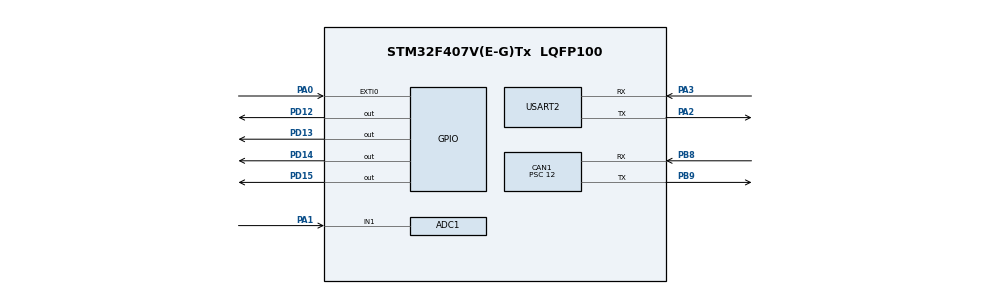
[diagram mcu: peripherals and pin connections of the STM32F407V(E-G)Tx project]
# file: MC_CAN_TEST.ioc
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ADC1.Channel-0\#ChannelRegularConversion=ADC_CHANNEL_1
ADC1.ContinuousConvMode=ENABLE
ADC1.NbrOfConversionFlag=1
ADC1.Rank-0\#ChannelRegularConversion=1
ADC1.SamplingTime-0\#ChannelRegularConversion=ADC_SAMPLETIME_3CYCLES
ADC1.ScanConvMode=ENABLE
ADC1.master=1
CAN1.BS1=CAN_BS1_11TQ
CAN1.BS2=CAN_BS2_2TQ
CAN1.CalculateBaudRate=250000
CAN1.CalculateTimeBit=4000
CAN1.CalculateTimeQuantum=285.7142857142857
CAN1.Prescaler=12
Mcu.Family=STM32F4
Mcu.Name=STM32F407V(E-G)Tx
Mcu.Package=LQFP100
NVIC.CAN1_RX0_IRQn=true\:0\:2\:false\:false\:true\:true\:true
NVIC.EXTI0_IRQn=true\:0\:1\:false\:false\:true\:true\:true
NVIC.PriorityGroup=NVIC_PRIORITYGROUP_0
PA0-WKUP.Signal=GPXTI0
PA1.Signal=ADCx_IN1
PA2.Mode=Asynchronous
PA2.Signal=USART2_TX
PA3.Mode=Asynchronous
PA3.Signal=USART2_RX
PB8.Mode=CAN_Activate
PB8.Signal=CAN1_RX
PB9.Mode=CAN_Activate
PB9.Signal=CAN1_TX
PD12.Signal=GPIO_Output
PD13.Signal=GPIO_Output
PD14.Signal=GPIO_Output
PD15.Signal=GPIO_Output
PH0-OSC_IN.Mode=HSE-External-Oscillator
PH0-OSC_IN.Signal=RCC_OSC_IN
PH1-OSC_OUT.Mode=HSE-External-Oscillator
PH1-OSC_OUT.Signal=RCC_OSC_OUT
ProjectManager.HeapSize=0x200
ProjectManager.StackSize=0x400
ProjectManager.TargetToolchain=STM32CubeIDE
RCC.48MHZClocksFreq_Value=48000000
RCC.AHBFreq_Value=168000000
RCC.APB1CLKDivider=RCC_HCLK_DIV4
RCC.APB1Freq_Value=42000000
RCC.APB1TimFreq_Value=84000000
RCC.APB2CLKDivider=RCC_HCLK_DIV2
RCC.APB2Freq_Value=84000000
RCC.APB2TimFreq_Value=168000000
RCC.CortexFreq_Value=168000000
RCC.HCLKFreq_Value=168000000
RCC.HSE_VALUE=8000000
RCC.HSI_VALUE=16000000
RCC.LSE_VALUE=32768
RCC.PLLM=4
RCC.PLLN=168
RCC.PLLQ=7
RCC.PLLSourceVirtual=RCC_PLLSOURCE_HSE
RCC.SYSCLKFreq_VALUE=168000000
RCC.SYSCLKSource=RCC_SYSCLKSOURCE_PLLCLK
RCC.VCOOutputFreq_Value=336000000
SH.ADCx_IN1.0=ADC1_IN1,IN1
USART2.VirtualMode=VM_ASYNC
board=STM32F407G-DISC1

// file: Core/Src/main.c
/* USER CODE BEGIN Header */
/**
 ******************************************************************************
 * @file           : main.c
 * @brief          : Main program body
 ******************************************************************************
 * @attention
 *
 * <h2><center>&copy; Copyright (c) 2021 STMicroelectronics.
 * All rights reserved.</center></h2>
 *
 * This software component is licensed by ST under Ultimate Liberty license
 * SLA0044, the "License"; You may not use this file except in compliance with
 * the License. You may obtain a copy of the License at:
 *                             www.st.com/SLA0044
 *
 ******************************************************************************
 */
/* USER CODE END Header */
#include "main.h"
#include "usb_device.h"

ADC_HandleTypeDef hadc1;

CAN_HandleTypeDef hcan1;

UART_HandleTypeDef huart2;

/* USER CODE BEGIN PV */
CAN_TxHeaderTypeDef pTxHeader; //CAN Tx Header
CAN_RxHeaderTypeDef pRxHeader; //CAN Rx Header
uint32_t pTxMailbox;
CAN_FilterTypeDef sFilterConfig; //CAN filter configuration

uint32_t MC_RX = 0x181;
uint32_t MC_TX = 0x201;

uint8_t sensor_raw;
// Byte 0: REG ID, Byte 1,2: Data
uint8_t rcvData[8];
uint8_t tData[8];
uint32_t rcvDataVal;
/* USER CODE END PV */

void SystemClock_Config(void);
static void MX_GPIO_Init(void);
static void MX_CAN1_Init(void);
static void MX_ADC1_Init(void);
static void MX_USART2_UART_Init(void);
/* USER CODE BEGIN PFP */
static void CAN_TxHeader_Init(CAN_TxHeaderTypeDef *pTxHeader, uint32_t dlc, uint32_t ide, uint32_t rtr, uint32_t stdId);
static void CAN_Filter_Init(CAN_HandleTypeDef *hcan, CAN_FilterTypeDef *sFilterConfig, uint32_t fifo, uint32_t highId, uint32_t lowId, uint32_t highMask, uint32_t lowMask, uint32_t scale);
HAL_StatusTypeDef CANsend(CAN_HandleTypeDef *hcan, CAN_TxHeaderTypeDef *pTxHeader, uint8_t data[], uint32_t *pTxMailbox);
/* USER CODE END PFP */

int main(void)
{

  /* MCU Configuration--------------------------------------------------------*/

  /* Reset of all peripherals, Initializes the Flash interface and the Systick. */
  HAL_Init();

  /* Configure the system clock */
  SystemClock_Config();

  /* Initialize all configured peripherals */
  MX_GPIO_Init();
  MX_CAN1_Init();
  MX_ADC1_Init();
  MX_USART2_UART_Init();
  MX_USB_DEVICE_Init();
  /* USER CODE BEGIN 2 */

	//Initialize CAN header - standard id type, set standard Id = filter ID of other device
	CAN_TxHeader_Init(&pTxHeader, 3, CAN_ID_STD, CAN_RTR_DATA, MC_TX);

	//Initialize CAN filter - filter ID = TxHeader Id of other device, 32 bit scale. Enables and configs filter.
	CAN_Filter_Init(&hcan1, &sFilterConfig, CAN_FILTER_FIFO0, MC_RX, 0, 0, 0, CAN_FILTERSCALE_32BIT);

	//start CAN
	HAL_CAN_Start(&hcan1);

	//interrupt on message pending
	HAL_CAN_ActivateNotification(&hcan1, CAN_IT_RX_FIFO0_MSG_PENDING);

  /* USER CODE END 2 */

  /* Infinite loop */
  /* USER CODE BEGIN WHILE */
	while (1)
	{
		HAL_ADC_Start(&hadc1);
		HAL_ADC_PollForConversion(&hadc1, 1000);
		sensor_raw = HAL_ADC_GetValue(&hadc1);
    /* USER CODE END WHILE */

	}
}

void SystemClock_Config(void)
{
  RCC_OscInitTypeDef RCC_OscInitStruct = {0};
  RCC_ClkInitTypeDef RCC_ClkInitStruct = {0};

  /** Configure the main internal regulator output voltage
  */
  __HAL_RCC_PWR_CLK_ENABLE();
  __HAL_PWR_VOLTAGESCALING_CONFIG(PWR_REGULATOR_VOLTAGE_SCALE1);
  /** Initializes the RCC Oscillators according to the specified parameters
  * in the RCC_OscInitTypeDef structure.
  */
  RCC_OscInitStruct.OscillatorType = RCC_OSCILLATORTYPE_HSE;
  RCC_OscInitStruct.HSEState = RCC_HSE_ON;
  RCC_OscInitStruct.PLL.PLLState = RCC_PLL_ON;
  RCC_OscInitStruct.PLL.PLLSource = RCC_PLLSOURCE_HSE;
  RCC_OscInitStruct.PLL.PLLM = 13;
  RCC_OscInitStruct.PLL.PLLN = 168;
  RCC_OscInitStruct.PLL.PLLP = RCC_PLLP_DIV2;
  RCC_OscInitStruct.PLL.PLLQ = 7;
  if (HAL_RCC_OscConfig(&RCC_OscInitStruct) != HAL_OK)
  {
    Error_Handler();
  }
  /** Initializes the CPU, AHB and APB buses clocks
  */
  RCC_ClkInitStruct.ClockType = RCC_CLOCKTYPE_HCLK|RCC_CLOCKTYPE_SYSCLK
                              |RCC_CLOCKTYPE_PCLK1|RCC_CLOCKTYPE_PCLK2;
  RCC_ClkInitStruct.SYSCLKSource = RCC_SYSCLKSOURCE_PLLCLK;
  RCC_ClkInitStruct.AHBCLKDivider = RCC_SYSCLK_DIV1;
  RCC_ClkInitStruct.APB1CLKDivider = RCC_HCLK_DIV4;
  RCC_ClkInitStruct.APB2CLKDivider = RCC_HCLK_DIV2;

  if (HAL_RCC_ClockConfig(&RCC_ClkInitStruct, FLASH_LATENCY_5) != HAL_OK)
  {
    Error_Handler();
  }
}

static void MX_ADC1_Init(void)
{

  ADC_ChannelConfTypeDef sConfig = {0};

  /** Configure the global features of the ADC (Clock, Resolution, Data Alignment and number of conversion)
  */
  hadc1.Instance = ADC1;
  hadc1.Init.ClockPrescaler = ADC_CLOCK_SYNC_PCLK_DIV4;
  hadc1.Init.Resolution = ADC_RESOLUTION_12B;
  hadc1.Init.ScanConvMode = ENABLE;
  hadc1.Init.ContinuousConvMode = ENABLE;
  hadc1.Init.DiscontinuousConvMode = DISABLE;
  hadc1.Init.ExternalTrigConvEdge = ADC_EXTERNALTRIGCONVEDGE_NONE;
  hadc1.Init.ExternalTrigConv = ADC_SOFTWARE_START;
  hadc1.Init.DataAlign = ADC_DATAALIGN_RIGHT;
  hadc1.Init.NbrOfConversion = 1;
  hadc1.Init.DMAContinuousRequests = DISABLE;
  hadc1.Init.EOCSelection = ADC_EOC_SINGLE_CONV;
  if (HAL_ADC_Init(&hadc1) != HAL_OK)
  {
    Error_Handler();
  }
  /** Configure for the selected ADC regular channel its corresponding rank in the sequencer and its sample time.
  */
  sConfig.Channel = ADC_CHANNEL_1;
  sConfig.Rank = 1;
  sConfig.SamplingTime = ADC_SAMPLETIME_3CYCLES;
  if (HAL_ADC_ConfigChannel(&hadc1, &sConfig) != HAL_OK)
  {
    Error_Handler();
  }

}

static void MX_CAN1_Init(void)
{

  hcan1.Instance = CAN1;
  hcan1.Init.Prescaler = 12;
  hcan1.Init.Mode = CAN_MODE_NORMAL;
  hcan1.Init.SyncJumpWidth = CAN_SJW_1TQ;
  hcan1.Init.TimeSeg1 = CAN_BS1_11TQ;
  hcan1.Init.TimeSeg2 = CAN_BS2_2TQ;
  hcan1.Init.TimeTriggeredMode = DISABLE;
  hcan1.Init.AutoBusOff = DISABLE;
  hcan1.Init.AutoWakeUp = DISABLE;
  hcan1.Init.AutoRetransmission = DISABLE;
  hcan1.Init.ReceiveFifoLocked = DISABLE;
  hcan1.Init.TransmitFifoPriority = DISABLE;
  if (HAL_CAN_Init(&hcan1) != HAL_OK)
  {
    Error_Handler();
  }

}

static void MX_USART2_UART_Init(void)
{

  huart2.Instance = USART2;
  huart2.Init.BaudRate = 115200;
  huart2.Init.WordLength = UART_WORDLENGTH_8B;
  huart2.Init.StopBits = UART_STOPBITS_1;
  huart2.Init.Parity = UART_PARITY_NONE;
  huart2.Init.Mode = UART_MODE_TX_RX;
  huart2.Init.HwFlowCtl = UART_HWCONTROL_NONE;
  huart2.Init.OverSampling = UART_OVERSAMPLING_16;
  if (HAL_UART_Init(&huart2) != HAL_OK)
  {
    Error_Handler();
  }

}

static void MX_GPIO_Init(void)
{
  GPIO_InitTypeDef GPIO_InitStruct = {0};

  /* GPIO Ports Clock Enable */
  __HAL_RCC_GPIOH_CLK_ENABLE();
  __HAL_RCC_GPIOA_CLK_ENABLE();
  __HAL_RCC_GPIOD_CLK_ENABLE();
  __HAL_RCC_GPIOB_CLK_ENABLE();

  /*Configure GPIO pin Output Level */
  HAL_GPIO_WritePin(GPIOD, GPIO_PIN_12|GPIO_PIN_13|GPIO_PIN_14|GPIO_PIN_15, GPIO_PIN_RESET);

  /*Configure GPIO pin : PA0 */
  GPIO_InitStruct.Pin = GPIO_PIN_0;
  GPIO_InitStruct.Mode = GPIO_MODE_IT_RISING;
  GPIO_InitStruct.Pull = GPIO_NOPULL;
  HAL_GPIO_Init(GPIOA, &GPIO_InitStruct);

  /*Configure GPIO pins : PD12 PD13 PD14 PD15 */
  GPIO_InitStruct.Pin = GPIO_PIN_12|GPIO_PIN_13|GPIO_PIN_14|GPIO_PIN_15;
  GPIO_InitStruct.Mode = GPIO_MODE_OUTPUT_PP;
  GPIO_InitStruct.Pull = GPIO_NOPULL;
  GPIO_InitStruct.Speed = GPIO_SPEED_FREQ_LOW;
  HAL_GPIO_Init(GPIOD, &GPIO_InitStruct);

  /* EXTI interrupt init*/
  HAL_NVIC_SetPriority(EXTI0_IRQn, 0, 1);
  HAL_NVIC_EnableIRQ(EXTI0_IRQn);

}

/* USER CODE BEGIN 4 */
static void CAN_TxHeader_Init(CAN_TxHeaderTypeDef *pTxHeader, uint32_t dlc,
		uint32_t ide, uint32_t rtr, uint32_t stdId)
{
	pTxHeader->DLC = dlc; // 'dlc' bytes of data
	pTxHeader->IDE = ide;
	pTxHeader->RTR = rtr;
	pTxHeader->StdId = stdId; //set standard identifier.
}

/**
 * @brief CAN Filter Initialization Function
 * @param hcan          : pointer to a CAN_HandleTypeDef structure that contains the configuration information for the specified CAN.
 *        sFilterConfig : pointer to a CAN_FilterTypeDef structure.
 * 	   fifo          : Specifies the FIFO (0 or 1) which will be assigned to the filter. This parameter can be a value of CAN_filter_FIFO
 * 	   highID        : Specifies the filter identification number (MSBs for a 32-bit configuration, first one for a 16-bit configuration). This parameter can be a value between 0x0000 and 0xFFFF
 * 	   lowID         : Specifies the filter identification number (LSBs for a 32-bit configuration, second one for a 16-bit configuration). This parameter can be a value between 0x0000 and 0xFFFF
 * 	   highMask      : Specifies the filter mask number or identification number, according to the mode (MSBs for a 32-bit configuration, first one for a 16-bit configuration). This parameter can be a value between 0x0000 and 0xFFFF
 * 	   lowMask       : Specifies the filter mask number or identification number, according to the mode (LSBs for a 32-bit configuration, second one for a 16-bit configuration). This parameter can be a value between 0x0000 and 0xFFFF
 * 	   scale         : Specifies the filter scale. This parameter can be a value of CAN_filter_scale
 * @retval None
 */
static void CAN_Filter_Init(CAN_HandleTypeDef *hcan,
		CAN_FilterTypeDef *sFilterConfig, uint32_t fifo, uint32_t highId,
		uint32_t lowId, uint32_t highMask, uint32_t lowMask, uint32_t scale)
{
	sFilterConfig->FilterFIFOAssignment = fifo;
	sFilterConfig->FilterIdHigh = highId << 5; //must be shifted 5 bits to the left according to reference manual
	sFilterConfig->FilterIdLow = lowId;
	sFilterConfig->FilterMaskIdHigh = highMask;
	sFilterConfig->FilterMaskIdLow = lowMask;
	sFilterConfig->FilterScale = scale;
	sFilterConfig->FilterActivation = CAN_FILTER_ENABLE; //enable activation

	HAL_CAN_ConfigFilter(hcan, sFilterConfig); //config CAN filter
}

/**
 * @brief CAN Transmit (after header, filter config)
 * @param hcan       : pointer to a CAN_HandleTypeDef structure that contains the configuration information for the specified CAN.
 *        pTxHeader  : pointer to a CAN_TxHeaderTypeDef structure.
 *        data       : array containing the payload of the Tx frame.
 *        pTxMailbox : pointer to a variable where the function will return the TxMailbox used to store the Tx message. This parameter can be a value of @arg CAN_Tx_Mailboxes.
 * @retval None
 */
HAL_StatusTypeDef CANsend(CAN_HandleTypeDef *hcan,
		CAN_TxHeaderTypeDef *pTxHeader, uint8_t data[], uint32_t *pTxMailbox)
{
	return (HAL_CAN_AddTxMessage(hcan, pTxHeader, data, pTxMailbox)); //transmit over CAN, return HAL status
}
/* USER CODE END 4 */

void Error_Handler(void)
{
	__disable_irq();
	while (1)
	{
	}
}
